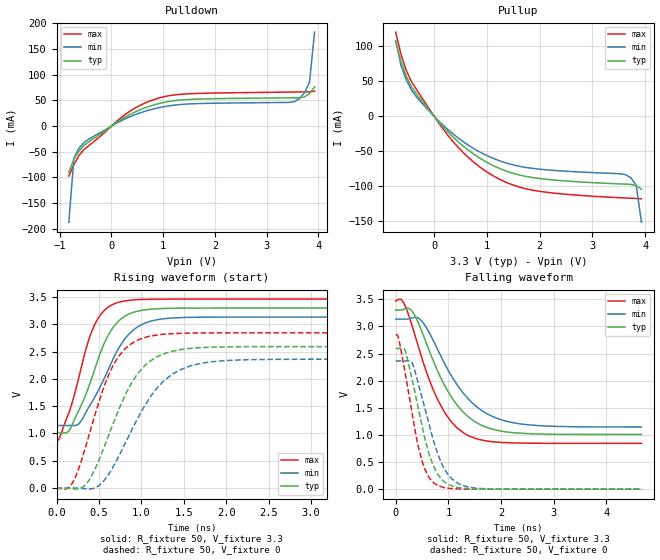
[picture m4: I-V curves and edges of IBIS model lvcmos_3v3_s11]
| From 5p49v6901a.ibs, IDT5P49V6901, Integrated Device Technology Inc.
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[Model]   lvcmos_3v3_s11
Model_type   Output
Polarity   Non-Inverting
|   typ   min   max
C_comp   2pF   1.5pF   2.5pF
Vmeas = 1.65V
Rref = 50
Cref = 0
Vref = 1.65V
|   typ   min   max
[Voltage range]   3.3V   3.135V   3.465V
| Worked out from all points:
|   slope of the pulldown table from 0 to 0.495 V, typ, clamps not added: 16.9 ohm
|   slope of the pullup table from 0 to 0.495 V, typ, clamps not added: 12.6 ohm
|   rising waveform, R_fixture 50, V_fixture 3.3: 20-80 % time 348ps typ, 402ps min, 290ps max; typ from 1.01 V to 3.3 V
|   falling waveform, R_fixture 50, V_fixture 3.3: 20-80 % time 716ps typ, 792ps min, 629ps max; typ from 3.3 V to 1.01 V
|   rising waveform, R_fixture 50, V_fixture 0: 20-80 % time 446ps typ, 522ps min, 371ps max; typ from 0 V to 2.59 V
|   falling waveform, R_fixture 50, V_fixture 0: 20-80 % time 381ps typ, 427ps min, 330ps max; typ from 2.59 V to 0 V
[Pulldown]
|Voltage   I (typ)   I (min)   I (max)
|Note, modeling breaks down at 250mA and above.  This is well beyond the functional   |
|operating range of the device.  Should this scenario occur, catastrophic failure and   |
|possible damage to the device and/or board is of higher concern than the I-V curve   |
|behavior.  The IBIS checker will flag currents in excess of 10A with warnings.  Lines   |
|with currents in excess of 0.35 A have been commented out.  The points still remain|
|available to the user if the user desires to use them.   |
|-3.30000e+00   -4.58626e+02   -3.98855e+02   -5.58913e+02
|-3.20100e+00   -4.38670e+02   -3.81813e+02   -5.34126e+02
|-3.10200e+00   -4.18718e+02   -3.64776e+02   -5.09343e+02
|-3.00300e+00   -3.98770e+02   -3.47745e+02   -4.84563e+02
|-2.90400e+00   -3.78827e+02   -3.30720e+02   -4.59787e+02
|-2.80500e+00   -3.58890e+02   -3.13701e+02   -4.35015e+02
|-2.70600e+00   -3.38959e+02   -2.96690e+02   -4.10248e+02
|-2.60700e+00   -3.19035e+02   -2.79688e+02   -3.85486e+02
|-2.50800e+00   -2.99119e+02   -2.62696e+02   -3.60731e+02
|-2.40900e+00   -2.79213e+02   -2.45715e+02   -3.35984e+02
|-2.31000e+00   -2.59319e+02   -2.28747e+02   -3.11245e+02
|-2.21100e+00   -2.39437e+02   -2.11796e+02   -2.86516e+02
|-2.11200e+00   -2.19572e+02   -1.94864e+02   -2.61800e+02
|-2.01300e+00   -1.99726e+02   -1.77955e+02   -2.37100e+02
|-1.91400e+00   -1.79905e+02   -1.61075e+02   -2.12419e+02
|-1.81500e+00   -1.60116e+02   -1.44233e+02   -1.87763e+02
|-1.71600e+00   -1.40369e+02   -1.27441e+02   -1.63140e+02
|-1.61700e+00   -1.20682e+02   -1.10717e+02   -1.38565e+02
|-1.51800e+00   -1.01080e+02   -9.40899e+01   -1.14061e+02
|-1.41900e+00   -8.16135e+01   -7.76121e+01   -8.96701e+01
|-1.32000e+00   -6.23864e+01   -6.13830e+01   -6.54941e+01
|-1.22100e+00   -4.36066e+01   -4.55730e+01   -4.17841e+01
|-1.12200e+00   -2.55446e+01   -3.03740e+01   -1.89497e+01
|-1.02300e+00   -8.13369e+00   -1.57511e+01   -1.01906e+00
|-9.24000e-01   -3.55892e-01   -2.38948e+00   -1.27879e-01
-825mV    -89.74mA   -186.9mA   -97.05mA
-726mV    -64.34mA   -62.46mA   -75.03mA
-627mV    -48.3mA    -42.65mA   -56.86mA
-528mV    -37.22mA   -31.89mA   -45.33mA
363mV     22.88mA    18.45mA    29.33mA
957mV     44.74mA    36.62mA    55.73mA
1.551V    52.05mA    43.3mA     63.04mA
3.531V    55.03mA    47.39mA    66.19mA
3.63V     55.21mA    52.95mA    66.32mA
3.729V    56.59mA    64.36mA    66.46mA
3.828V    63.02mA    84.81mA    66.64mA
3.927V    76.26mA    182.8mA    67.99mA
| 4.02600e+00   9.63336e-02   1.95544e+00   7.56685e-02
| 4.12500e+00   1.29319e-01   1.96109e+01   9.19025e-02
| 4.22400e+00   6.62462e-01   4.21550e+01   1.15435e-01
| 4.32300e+00   1.51637e+01   6.47670e+01   1.37492e-01
| 4.42200e+00   4.22442e+01   8.74545e+01   2.35006e-01
| 4.52100e+00   6.94172e+01   1.10195e+02   8.92943e+00
| 4.62000e+00   9.66780e+01   1.32968e+02   4.35589e+01
| 4.71900e+00   1.23991e+02   1.55761e+02   7.83218e+01
| 4.81800e+00   1.51333e+02   1.78569e+02   1.13180e+02
| 4.91700e+00   1.78693e+02   2.01386e+02   1.48085e+02
| 5.01600e+00   2.06065e+02   2.24210e+02   1.83014e+02
| 5.11500e+00   2.33446e+02   2.47041e+02   2.17958e+02
| 5.21400e+00   2.60834e+02   2.69877e+02   2.52912e+02
| 5.31300e+00   2.88228e+02   2.92717e+02   2.87874e+02
| 5.41200e+00   3.15625e+02   3.15560e+02   3.22841e+02
| 5.51100e+00   3.43027e+02   3.38407e+02   3.57813e+02
| 5.61000e+00   3.70432e+02   3.61256e+02   3.92789e+02
| 5.70900e+00   3.97841e+02   3.84108e+02   4.27769e+02
| 5.80800e+00   4.25252e+02   4.06963e+02   4.62752e+02
| 5.90700e+00   4.52666e+02   4.29821e+02   4.97738e+02
| 6.00600e+00   4.80082e+02   4.52680e+02   5.32727e+02
| 6.10500e+00   5.07501e+02   4.75543e+02   5.67718e+02
| 6.20400e+00   5.34922e+02   4.98407e+02   6.02711e+02
| 6.30300e+00   5.62345e+02   5.21273e+02   6.37705e+02
| 6.40200e+00   5.89770e+02   5.44142e+02   6.72701e+02
| 6.50100e+00   6.17197e+02   5.67013e+02   7.07699e+02
| 6.60000e+00   6.44626e+02   5.89886e+02   7.42698e+02
[Pullup]
|Voltage   I (typ)   I (min)   I (max)
|Note, modeling breaks down at 250mA and above.  This is well beyond the functional   |
|operating range of the device.  Should this scenario occur, catastrophic failure and   |
|possible damage to the device and/or board is of higher concern than the I-V curve   |
|behavior.  The IBIS checker will flag currents in excess of 10A with warnings.  Lines   |
|with currents in excess of 0.35 A have been commented out.  The points still remain|
|available to the user if the user desires to use them.   |
|-3.30000e+00   6.44680e+02   5.51825e+02   8.01095e+02
|-3.20100e+00   6.17254e+02   5.28958e+02   7.66095e+02
|-3.10200e+00   5.89830e+02   5.06093e+02   7.31096e+02
|-3.00300e+00   5.62407e+02   4.83230e+02   6.96098e+02
|-2.90400e+00   5.34987e+02   4.60368e+02   6.61102e+02
|-2.80500e+00   5.07568e+02   4.37509e+02   6.26108e+02
|-2.70600e+00   4.80150e+02   4.14651e+02   5.91115e+02
|-2.60700e+00   4.52735e+02   3.91796e+02   5.56124e+02
|-2.50800e+00   4.25322e+02   3.68942e+02   5.21136e+02
|-2.40900e+00   3.97911e+02   3.46091e+02   4.86149e+02
|-2.31000e+00   3.70503e+02   3.23243e+02   4.51165e+02
|-2.21100e+00   3.43097e+02   3.00397e+02   4.16183e+02
|-2.11200e+00   3.15694e+02   2.77554e+02   3.81204e+02
|-2.01300e+00   2.88295e+02   2.54715e+02   3.46229e+02
|-1.91400e+00   2.60900e+02   2.31881e+02   3.11257e+02
|-1.81500e+00   2.33510e+02   2.09052e+02   2.76290e+02
|-1.71600e+00   2.06127e+02   1.86229e+02   2.41329e+02
|-1.61700e+00   1.78751e+02   1.63415e+02   2.06375e+02
|-1.51800e+00   1.51388e+02   1.40613e+02   1.71432e+02
|-1.41900e+00   1.24042e+02   1.17829e+02   1.36506e+02
|-1.32000e+00   9.67252e+01   9.50724e+01   1.01609e+02
|-1.22100e+00   6.94599e+01   7.23604e+01   6.67700e+01
|-1.12200e+00   4.22820e+01   4.97173e+01   3.20469e+01
|-1.02300e+00   1.51962e+01   2.71494e+01   2.11287e+00
|-9.24000e-01   6.89030e-01   5.34223e+00   1.97623e-01
|-8.25000e-01   1.48916e-01   3.54714e-01   1.54087e-01
-726mV    106.9mA    108.2mA    120.1mA
-627mV    78.63mA    72.64mA    88.74mA
-528mV    57.36mA    52.3mA     65.5mA
-330mV    31.45mA    27.24mA    37.82mA
363mV     -30.02mA   -25.58mA   -36.52mA
957mV     -64.05mA   -54.65mA   -77.43mA
1.353V    -77.99mA   -66.51mA   -94.06mA
1.848V    -87.45mA   -74.38mA   -105.4mA
3.63V     -97.08mA   -83.63mA   -116.9mA
3.729V    -97.47mA   -88.18mA   -117.2mA
3.828V    -98.9mA    -99mA      -117.5mA
3.927V    -104.4mA   -151.4mA   -117.9mA
| 4.02600e+00   -1.15410e-01   -9.65481e-01   -1.19366e-01
| 4.12500e+00   -1.36603e-01   -1.09884e+01   -1.26324e-01
| 4.22400e+00   -3.99361e-01   -2.54841e+01   -1.40663e-01
| 4.32300e+00   -8.17474e+00   -4.04654e+01   -1.58277e-01
| 4.42200e+00   -2.55843e+01   -5.60873e+01   -2.17491e-01
| 4.52100e+00   -4.36450e+01   -7.21990e+01   -4.28595e+00
| 4.62000e+00   -6.24226e+01   -8.86071e+01   -2.64922e+01
| 4.71900e+00   -8.16508e+01   -1.05189e+02   -4.96573e+01
| 4.81800e+00   -1.01115e+02   -1.21884e+02   -7.35635e+01
| 4.91700e+00   -1.20715e+02   -1.38656e+02   -9.78285e+01
| 5.01600e+00   -1.40403e+02   -1.55482e+02   -1.22263e+02
| 5.11500e+00   -1.60149e+02   -1.72350e+02   -1.46794e+02
| 5.21400e+00   -1.79938e+02   -1.89250e+02   -1.71387e+02
| 5.31300e+00   -1.99760e+02   -2.06175e+02   -1.96022e+02
| 5.41200e+00   -2.19606e+02   -2.23121e+02   -2.20688e+02
| 5.51100e+00   -2.39472e+02   -2.40084e+02   -2.45378e+02
| 5.61000e+00   -2.59355e+02   -2.57061e+02   -2.70086e+02
| 5.70900e+00   -2.79251e+02   -2.74051e+02   -2.94808e+02
| 5.80800e+00   -2.99159e+02   -2.91052e+02   -3.19543e+02
| 5.90700e+00   -3.19077e+02   -3.08062e+02   -3.44288e+02
| 6.00600e+00   -3.39003e+02   -3.25080e+02   -3.69042e+02
| 6.10500e+00   -3.58937e+02   -3.42106e+02   -3.93803e+02
| 6.20400e+00   -3.78878e+02   -3.59138e+02   -4.18571e+02
| 6.30300e+00   -3.98826e+02   -3.76177e+02   -4.43346e+02
| 6.40200e+00   -4.18779e+02   -3.93221e+02   -4.68125e+02
| 6.50100e+00   -4.38737e+02   -4.10271e+02   -4.92910e+02
| 6.60000e+00   -4.58699e+02   -4.27325e+02   -5.17700e+02
[Ramp]
|   typ   min   max
dV/dt_r   1.567/0.448n   1.427/0.524n   1.72/0.372n
dV/dt_f   1.396/0.72n  1.213/0.797n   1.595/0.632n
R_load =   50
[Rising Waveform]
R_fixture = 50
V_fixture = 3.3   |Vcc_typ
V_fixture_min = 3.135 |Vcc_min
V_fixture_max = 3.465 |Vcc_max
C_fixture = 0.0p
| Time   typ   min   max
| 0.00000e+00   1.00813e+00   1.14515e+00   8.44568e-01
| 2.69541e-12   1.00813e+00   1.14515e+00   8.44568e-01
| 4.88539e-12   1.00813e+00   1.14515e+00   8.44568e-01
| 5.15560e-12   1.00813e+00   1.14515e+00   8.44568e-01
| 8.43814e-12   1.00813e+00   1.14515e+00   8.44568e-01
| 1.48885e-11   1.00813e+00   1.14515e+00   8.44568e-01
| 1.56443e-11   1.00813e+00   1.14515e+00   8.44568e-01
| 2.89352e-11   1.00813e+00   1.14515e+00   8.44568e-01
| 4.35521e-11   1.00813e+00   1.14515e+00   8.44568e-01
| 4.98146e-11   1.00813e+00   1.14515e+00   8.44568e-01
| 5.87208e-11   1.00813e+00   1.14515e+00   8.44568e-01
| 7.00000e-11   1.00813e+00   1.14515e+00   8.44568e-01
| 7.43355e-11   1.00813e+00   1.14515e+00   8.44568e-01
| 7.98941e-11   1.00813e+00   1.14515e+00   8.44568e-01
| 8.04812e-11   1.00813e+00   1.14515e+00   8.44568e-01
| 8.54765e-11   1.00813e+00   1.14515e+00   8.44568e-01
| 9.54712e-11   1.00813e+00   1.14515e+00   8.44568e-01
| 9.66941e-11   1.00813e+00   1.14515e+00   8.44568e-01
| 1.09694e-10   1.00813e+00   1.14515e+00   8.44568e-01
| 1.16904e-10   1.00813e+00   1.14515e+00   8.44568e-01
| 1.22050e-10   1.00813e+00   1.14515e+00   8.44568e-01
| 1.33756e-10   1.00813e+00   1.14515e+00   8.44568e-01
| 1.42319e-10   1.00813e+00   1.14515e+00   8.44568e-01
| 1.49876e-10   1.00813e+00   1.14515e+00   8.44568e-01
| 1.59675e-10   1.00813e+00   1.14515e+00   8.44568e-01
| 1.71924e-10   1.00813e+00   1.14515e+00   8.44568e-01
| 1.80502e-10   1.00813e+00   1.14515e+00   8.44568e-01
| 1.93342e-10   1.00813e+00   1.14515e+00   8.44568e-01
| 2.03187e-10   1.00813e+00   1.14515e+00   8.44568e-01
| 2.12788e-10   1.00813e+00   1.14515e+00   8.44568e-01
| 2.20117e-10   1.00813e+00   1.14515e+00   8.44568e-01
| 2.25959e-10   1.00813e+00   1.14515e+00   8.44568e-01
| 2.28188e-10   1.00813e+00   1.14515e+00   8.44568e-01
| 2.36412e-10   1.00813e+00   1.14515e+00   8.44568e-01
| 2.43714e-10   1.00813e+00   1.14515e+00   8.44568e-01
| 2.46567e-10   1.00813e+00   1.14515e+00   8.44568e-01
| 2.54564e-10   1.00813e+00   1.14515e+00   8.44568e-01
| 2.64893e-10   1.00813e+00   1.14515e+00   8.44568e-01
| 2.65919e-10   1.00813e+00   1.14515e+00   8.44568e-01
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0s        1.008V     1.145V     844.6mV
163.1ps   1.088V     1.145V     1.456V
271.8ps   1.452V     1.191V     2.084V
373.4ps   1.829V     1.465V     2.686V
444.1ps   2.15V      1.647V     2.977V
558.2ps   2.64V      1.995V     3.249V
717ps     3.037V     2.52V      3.399V
972.5ps   3.249V     2.972V     3.456V
1.336ns   3.295V     3.115V     3.464V
4.665ns   3.3V       3.135V     3.465V
[Falling Waveform]
R_fixture = 50
V_fixture = 3.3   |Vcc_typ
V_fixture_min = 3.135 |Vcc_min
V_fixture_max = 3.465 |Vcc_max
C_fixture = 0.0p
| Time   typ   min   max
| 0.00000e+00   3.30000e+00   3.13500e+00   3.46500e+00
| 2.69541e-12   3.30000e+00   3.13500e+00   3.46500e+00
| 4.88539e-12   3.30000e+00   3.13500e+00   3.46500e+00
| 5.15560e-12   3.30000e+00   3.13500e+00   3.46500e+00
| 8.43814e-12   3.30000e+00   3.13500e+00   3.46500e+00
| 1.48885e-11   3.30000e+00   3.13500e+00   3.46500e+00
| 1.56443e-11   3.30000e+00   3.13500e+00   3.46500e+00
| 2.89352e-11   3.30000e+00   3.13500e+00   3.46500e+00
| 4.35521e-11   3.30000e+00   3.13500e+00   3.46500e+00
| 4.98146e-11   3.30000e+00   3.13500e+00   3.46500e+00
| 5.87207e-11   3.30000e+00   3.13500e+00   3.46500e+00
| 7.00000e-11   3.30000e+00   3.13500e+00   3.46500e+00
| 7.43355e-11   3.30000e+00   3.13500e+00   3.46500e+00
| 7.98941e-11   3.30000e+00   3.13500e+00   3.46500e+00
| 8.04812e-11   3.30000e+00   3.13500e+00   3.46500e+00
| 8.54765e-11   3.30000e+00   3.13500e+00   3.46500e+00
| 9.54712e-11   3.30000e+00   3.13500e+00   3.46500e+00
| 9.66941e-11   3.30000e+00   3.13500e+00   3.46500e+00
| 1.09694e-10   3.30000e+00   3.13500e+00   3.46500e+00
| 1.16904e-10   3.30000e+00   3.13500e+00   3.46500e+00
| 1.22050e-10   3.30000e+00   3.13500e+00   3.46500e+00
| 1.33756e-10   3.30000e+00   3.13500e+00   3.46500e+00
| 1.42318e-10   3.30000e+00   3.13500e+00   3.46500e+00
| 1.49875e-10   3.30000e+00   3.13500e+00   3.46500e+00
| 1.59673e-10   3.30000e+00   3.13500e+00   3.46500e+00
| 1.72937e-10   3.30000e+00   3.13500e+00   3.46500e+00
| 1.80499e-10   3.30000e+00   3.13500e+00   3.46500e+00
| 1.94084e-10   3.30000e+00   3.13500e+00   3.46500e+00
| 2.03953e-10   3.30000e+00   3.13500e+00   3.46500e+00
| 2.17182e-10   3.30000e+00   3.13500e+00   3.46500e+00
| 2.22997e-10   3.30000e+00   3.13500e+00   3.46500e+00
| 2.32435e-10   3.30000e+00   3.13500e+00   3.46500e+00
| 2.41161e-10   3.30000e+00   3.13500e+00   3.46500e+00
| 2.46386e-10   3.30000e+00   3.13500e+00   3.46500e+00
| 2.56120e-10   3.30000e+00   3.13500e+00   3.46500e+00
| 2.57140e-10   3.30000e+00   3.13500e+00   3.46500e+00
| 2.66989e-10   3.30000e+00   3.13500e+00   3.46500e+00
| 2.77410e-10   3.30000e+00   3.13500e+00   3.46500e+00
| 2.83432e-10   3.30000e+00   3.13500e+00   3.46500e+00
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0s        3.3V       3.135V     3.465V
178.4ps   3.323V     3.135V     3.381V
314.2ps   3.272V     3.155V     3.003V
485.4ps   2.935V     3.107V     2.45V
681.8ps   2.442V     2.8V       1.905V
924ps     1.92V      2.324V     1.422V
1.364ns   1.346V     1.679V     993.5mV
1.724ns   1.14V      1.394V     888.5mV
2.279ns   1.037V     1.216V     850.8mV
4.665ns   1.008V     1.145V     844.6mV
[Rising Waveform]
R_fixture = 50
V_fixture = 0
C_fixture = 0.0p
| Time   typ   min   max
| 0.00000e+00   2.38922e-08   6.04307e-08   3.04013e-08
| 2.69541e-12   2.38928e-08   6.04313e-08   3.04019e-08
| 5.02196e-12   2.38933e-08   6.04317e-08   3.04024e-08
| 8.43814e-12   2.38939e-08   6.04323e-08   3.04029e-08
| 1.48885e-11   2.38940e-08   6.04329e-08   3.04024e-08
| 2.82261e-11   2.38916e-08   6.04313e-08   3.03997e-08
| 2.96292e-11   2.38914e-08   6.04311e-08   3.03994e-08
| 4.65264e-11   2.38885e-08   6.04278e-08   3.03985e-08
| 5.82632e-11   2.38858e-08   6.04236e-08   3.03966e-08
| 5.99073e-11   2.38849e-08   6.04221e-08   3.03962e-08
| 7.43093e-11   2.38731e-08   6.04054e-08   3.03887e-08
| 7.44096e-11   2.38730e-08   6.04053e-08   3.03887e-08
| 8.01162e-11   2.38724e-08   6.03982e-08   3.03965e-08
| 8.50865e-11   2.38893e-08   6.04041e-08   3.04290e-08
| 8.58855e-11   2.38922e-08   6.04086e-08   3.04412e-08
| 9.61972e-11   2.40299e-08   6.05121e-08   3.05978e-08
| 1.07592e-10   2.42392e-08   6.07310e-08   3.07507e-08
| 1.10532e-10   2.42813e-08   6.07874e-08   3.07285e-08
| 1.20263e-10   2.43166e-08   6.09004e-08   3.05635e-08
| 1.31586e-10   2.39713e-08   6.07197e-08   3.01694e-08
| 1.35499e-10   2.37748e-08   6.06370e-08   2.99417e-08
| 1.46539e-10   2.29496e-08   5.97383e-08   2.91165e-08
| 1.55369e-10   2.17466e-08   5.85780e-08   2.82206e-08
| 1.63542e-10   2.08224e-08   5.72555e-08   2.77175e-08
| 1.77096e-10   1.96396e-08   5.55755e-08   2.77913e-08
| 1.86474e-10   2.06641e-08   5.56657e-08   2.88603e-08
| 1.98457e-10   2.24648e-08   5.66936e-08   3.14333e-08
| 2.09942e-10   2.48230e-08   5.90302e-08   3.38288e-08
| 2.15324e-10   2.58379e-08   6.01254e-08   3.48187e-08
| 2.20167e-10   2.67512e-08   6.09776e-08   3.55985e-08
| 2.27556e-10   2.81645e-08   6.22962e-08   3.65251e-08
| 2.34644e-10   2.94061e-08   6.36251e-08   3.65996e-08
| 2.36605e-10   2.97283e-08   6.40387e-08   3.66201e-08
| 2.44185e-10   3.03296e-08   6.55662e-08   3.54291e-08
| 2.54086e-10   3.02433e-08   6.61606e-08   3.24023e-08
| 2.55652e-10   3.01860e-08   6.60895e-08   3.18817e-08
| 2.65464e-10   2.86994e-08   6.51907e-08   2.86957e-08
| 2.76364e-10   2.59369e-08   6.40734e-08   2.65096e-08
| 2.78193e-10   2.54653e-08   6.38552e-08   2.63603e-08
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0s        23.89nV    60.43nV    30.4nV
177.3ps   -11.25mV   239uV      69.2mV
360.4ps   93.21mV    -15.93mV   847.5mV
517.9ps   580.6mV    67.89mV    1.668V
661.3ps   1.156V     370.9mV    2.23V
799.1ps   1.666V     785.3mV    2.539V
973.9ps   2.129V     1.326V     2.724V
1.304ns   2.481V     2.015V     2.826V
1.689ns   2.574V     2.281V     2.843V
4.388ns   2.593V     2.362V     2.845V
[Falling Waveform]
R_fixture = 50
V_fixture = 0
C_fixture = 0.0p
| Time   typ   min   max
| 0.00000e+00   2.59298e+00   2.36182e+00   2.84510e+00
| 7.32302e-10   2.59297e+00   2.36182e+00   2.84511e+00
| 7.45695e-10   2.59297e+00   2.36182e+00   2.84508e+00
| 7.56189e-10   2.59297e+00   2.36182e+00   2.84503e+00
| 7.64187e-10   2.59298e+00   2.36182e+00   2.84500e+00
| 7.77879e-10   2.59298e+00   2.36182e+00   2.84494e+00
| 7.83323e-10   2.59298e+00   2.36182e+00   2.84490e+00
| 7.94249e-10   2.59298e+00   2.36182e+00   2.84473e+00
| 7.99140e-10   2.59298e+00   2.36182e+00   2.84484e+00
| 8.04546e-10   2.59298e+00   2.36182e+00   2.84526e+00
| 8.15034e-10   2.59298e+00   2.36182e+00   2.84675e+00
| 8.20447e-10   2.59298e+00   2.36182e+00   2.84765e+00
| 8.29195e-10   2.59298e+00   2.36182e+00   2.84888e+00
| 8.31001e-10   2.59298e+00   2.36182e+00   2.84909e+00
| 8.43486e-10   2.59297e+00   2.36182e+00   2.84902e+00
| 8.49021e-10   2.59296e+00   2.36182e+00   2.84794e+00
| 8.58621e-10   2.59294e+00   2.36182e+00   2.84330e+00
| 8.64367e-10   2.59292e+00   2.36182e+00   2.83895e+00
| 8.71604e-10   2.59290e+00   2.36182e+00   2.83010e+00
| 8.81730e-10   2.59288e+00   2.36182e+00   2.80961e+00
| 8.90308e-10   2.59286e+00   2.36182e+00   2.78202e+00
| 8.98875e-10   2.59283e+00   2.36182e+00   2.74576e+00
| 9.04944e-10   2.59279e+00   2.36182e+00   2.71738e+00
| 9.09833e-10   2.59276e+00   2.36182e+00   2.69386e+00
| 9.19578e-10   2.59290e+00   2.36182e+00   2.64433e+00
| 9.25960e-10   2.59327e+00   2.36182e+00   2.61037e+00
| 9.31767e-10   2.59380e+00   2.36182e+00   2.57938e+00
| 9.39231e-10   2.59458e+00   2.36181e+00   2.53963e+00
| 9.41250e-10   2.59479e+00   2.36181e+00   2.52902e+00
| 9.50043e-10   2.59561e+00   2.36181e+00   2.48327e+00
| 9.56343e-10   2.59594e+00   2.36180e+00   2.45110e+00
| 9.60684e-10   2.59598e+00   2.36180e+00   2.42893e+00
| 9.70149e-10   2.59512e+00   2.36178e+00   2.38078e+00
| 9.72950e-10   2.59474e+00   2.36177e+00   2.36651e+00
| 9.82633e-10   2.59143e+00   2.36175e+00   2.31683e+00
| 9.87619e-10   2.58908e+00   2.36175e+00   2.29094e+00
| 9.95857e-10   2.58273e+00   2.36173e+00   2.24778e+00
| 1.00338e-09   2.57414e+00   2.36173e+00   2.20766e+00
| 1.00674e-09   2.56889e+00   2.36172e+00   2.18978e+00
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0s        2.593V     2.362V     2.845V
55.14ps   2.593V     2.362V     2.782V
171.6ps   2.569V     2.362V     2.19V
316.7ps   2.001V     2.32V      1.364V
426.5ps   1.504V     1.955V     794.4mV
544ps     978.7mV    1.527V     390.7mV
780ps     301.3mV    702.6mV    79.13mV
1.023ns   75.15mV    234.5mV    13.45mV
1.354ns   10.7mV     44.41mV    1.13mV
4.665ns   -479.5nV   -668.8nV   -535.8nV
